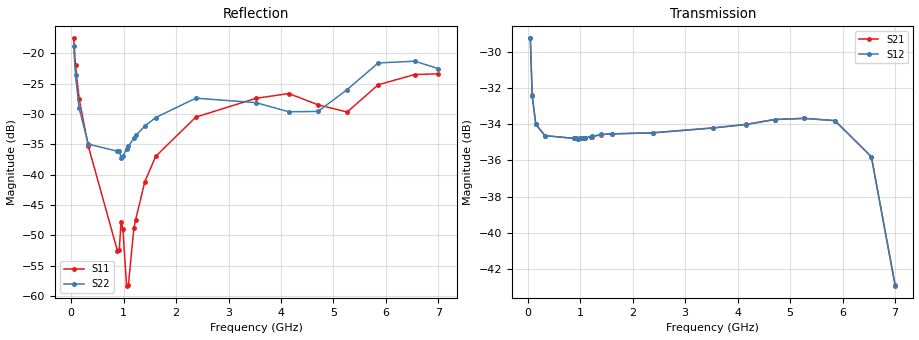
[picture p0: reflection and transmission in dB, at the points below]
! Integrated Device Technology
! Corporate Headquarters
! 6024 Silver Creek Valley Road
! San Jose, CA 95138  USA
! Phone:  1-408-284-8200
! Toll Free:  1-800-223-1366
! Webpage:  http://www.idt.com/
! Timing and RF Division
! 515 Groton Road, Suite 102
! Westford, MA 01886-6024
! Device:  F2258
! Description: Voltage Variable RF Attenuator
! Frequency:  50.0 -  6000.00 MHz
! Package:  3x3 mm Thin QFN Plastic Package: 16 pin
! Ports:  2 RF, 2 DC
!  Pin  1  = NC
!  Pin  2  = NC
!  Pin  3  = RF2  = Port 2
!  Pin  4  = GND
!  Pin  5  = Vdd
!  Pin  6  = NC
!  Pin  7  = VCTRL
!  Pin  8  = NC
!  Pin  9  = GND
!  Pin 10  = RF1  = Port 1
!  Pin 11  = NC
!  Pin 12  = NC
!  Pin 13  = NC
!  Pin 14  = NC
!  Pin 15  = NC
!  Pin 16  = NC
! Vcntrl:  1.950 Volts
! Vdd:  +3.300 Volts
! Current:  1.154 mA
! Data:  The device was measured on a the F2258 evaluation board which has
!  individual transmission lines to the RF pins.  Data was collected
!  using a calibrated network analyzer.  The evaluation board was
!  de-embedded using a TRL calibration technique.
!  The reference plane is the edge of the package pin.
! Misc:  SN 10
!  Action Tracker AT0285
! Date Measured:  2014-12-10
! Date:  2016-01-13  MJV
! Note:
!  Integrated Device Technology supplies this data as a sample of measured
!  data at the package pin for this product.  Your particular data for this
!  product may vary.
!  Data was taken at 25 degrees C.
!  Integrated Device Technology reserves the right to change this data at anytime.
!Freq_(GHz)  S11M_(dB)  S11P_(deg)  S21M_(dB)  S21P_(deg)  S12M_(dB)  S12P_(deg)  S22M_(dB)  S22P_(deg)
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# GHz S dB R 50
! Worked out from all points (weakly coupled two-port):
!   201 points, 50 MHz to 7 GHz, reference 50 ohm
!   highest |S21| = -29.26 dB at 50 MHz (marker M1); lowest = -42.9 dB at 7 GHz (marker M2)
!   lowest |S11| = -58.3 dB at 1.058 GHz (marker M3), VSWR 1.00, Z = 49.9 + j0.0526 ohm
!   |S11| at or under -10 dB: start of sweep to end of sweep
!   |S22| runs from -37.2 to -18.8 dB; largest |S21 - S12| = 7.5e-05
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0.05  -17.55 -110.9  -29.26 -65.8  -29.26 -65.8  -18.77 -106.4
0.08475  -21.98 -107.3  -32.41 -46.5  -32.42 -46.5  -23.66 -94.8
0.15425  -27.55 -107.8  -34.01 -28.2  -34.01 -28.2  -29.06 -79.9
0.328  -35.27 -114.6  -34.63 -14.9  -34.63 -14.9  -34.97 -46.9
0.884  -52.55 166.1  -34.78 -8.8  -34.78 -8.8  -36.14 7.3
0.91875  -52.36 149.6  -34.78 -8.7  -34.78 -8.7  -36.11 8.2
0.9535  -47.72 -161.5  -34.79 -8.7  -34.79 -8.6  -37.19 19.3
0.98825  -49.00 -174.0  -34.78 -8.6  -34.77 -8.6  -36.98 17.5
1.05775  -58.29 154.3  -34.76 -8.5  -34.76 -8.5  -35.71 17.4
1.0925  -58.16 116.5  -34.74 -8.5  -34.74 -8.5  -35.33 17.7
1.19675  -48.86 55.4  -34.70 -8.6  -34.70 -8.6  -34.03 17.3
1.2315  -47.42 45.1  -34.68 -8.6  -34.67 -8.6  -33.55 16.6
1.40525  -41.17 33.1  -34.57 -9.3  -34.56 -9.4  -32.00 17.7
1.61375  -36.97 32.5  -34.53 -10.5  -34.53 -10.5  -30.59 15.3
2.37825  -30.52 47.9  -34.47 -14.4  -34.48 -14.4  -27.40 18.2
3.525  -27.42 91.5  -34.20 -21.3  -34.21 -21.3  -28.14 44.0
4.1505  -26.64 104.9  -34.01 -25.9  -34.02 -25.9  -29.65 53.9
4.7065  -28.50 95.5  -33.74 -30.7  -33.74 -30.7  -29.58 34.4
5.2625  -29.68 54.1  -33.68 -36.8  -33.67 -36.8  -25.98 0.9
5.85325  -25.19 29.7  -33.80 -47.1  -33.80 -47.1  -21.60 -14.6
6.54825  -23.51 45.0  -35.79 -66.9  -35.80 -66.9  -21.31 -47.3
7  -23.39 84.4  -42.86 -62.9  -42.91 -62.7  -22.54 -126.9
